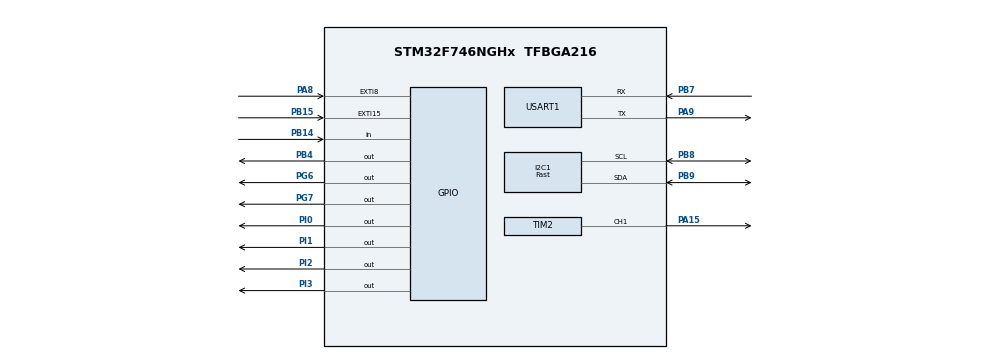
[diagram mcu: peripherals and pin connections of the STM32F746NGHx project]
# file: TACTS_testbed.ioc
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CORTEX_M7.CPU_DCache=Enabled
CORTEX_M7.CPU_ICache=Enabled
I2C1.I2C_Speed_Mode=I2C_Fast
I2C1.Timing=0x6000030D
Mcu.Family=STM32F7
Mcu.Name=STM32F746NGHx
Mcu.Package=TFBGA216
NVIC.EXTI15_10_IRQn=true\:0\:0\:false\:true\:true\:4\:true\:true\:true
NVIC.EXTI9_5_IRQn=true\:0\:0\:false\:true\:true\:5\:true\:true\:true
NVIC.I2C1_ER_IRQn=true\:0\:0\:false\:true\:true\:2\:true\:true\:true
NVIC.I2C1_EV_IRQn=true\:0\:0\:false\:true\:true\:3\:true\:true\:true
NVIC.PriorityGroup=NVIC_PRIORITYGROUP_4
NVIC.TIM2_IRQn=true\:0\:0\:false\:true\:true\:7\:true\:true\:true
NVIC.TIM7_IRQn=true\:0\:0\:false\:true\:true\:6\:true\:true\:true
NVIC.USART1_IRQn=true\:0\:0\:false\:true\:true\:1\:true\:true\:true
PA15.Signal=S_TIM2_CH1_ETR
PA8.GPIO_PuPd=GPIO_PULLUP
PA8.Signal=GPXTI8
PA9.Mode=Asynchronous
PA9.Signal=USART1_TX
PB14.Signal=GPIO_Input
PB15.GPIO_PuPd=GPIO_PULLUP
PB15.Signal=GPXTI15
PB4.Signal=GPIO_Output
PB7.Mode=Asynchronous
PB7.Signal=USART1_RX
PB8.Mode=I2C
PB8.Signal=I2C1_SCL
PB9.Mode=I2C
PB9.Signal=I2C1_SDA
PG6.Signal=GPIO_Output
PG7.Signal=GPIO_Output
PH0/OSC_IN.Mode=HSE-External-Clock-Source
PH0/OSC_IN.Signal=RCC_OSC_IN
PH1/OSC_OUT.Mode=HSE-External-Clock-Source
PH1/OSC_OUT.Signal=RCC_OSC_OUT
PI0.Signal=GPIO_Output
PI1.Signal=GPIO_Output
PI2.Signal=GPIO_Output
PI3.Signal=GPIO_Output
ProjectManager.HeapSize=0x800
ProjectManager.StackSize=0x800
ProjectManager.TargetToolchain=STM32CubeIDE
RCC.AHBFreq_Value=216000000
RCC.APB1CLKDivider=RCC_HCLK_DIV4
RCC.APB1Freq_Value=54000000
RCC.APB1TimFreq_Value=108000000
RCC.APB2CLKDivider=RCC_HCLK_DIV2
RCC.APB2Freq_Value=108000000
RCC.APB2TimFreq_Value=216000000
RCC.CortexFreq_Value=216000000
RCC.HCLKFreq_Value=216000000
RCC.HSE_VALUE=8000000
RCC.HSI_VALUE=16000000
RCC.LSE_VALUE=32768
RCC.PLLM=4
RCC.PLLN=216
RCC.PLLSourceVirtual=RCC_PLLSOURCE_HSE
RCC.SYSCLKFreq_VALUE=216000000
RCC.SYSCLKSource=RCC_SYSCLKSOURCE_PLLCLK
RCC.USBFreq_Value=216000000
RCC.VCOOutputFreq_Value=432000000
SH.S_TIM2_CH1_ETR.0=TIM2_CH1,PWM Generation1 CH1
STMicroelectronics.X-CUBE-AI.8.1.0.ActivationBufferSizeList=4504
STMicroelectronics.X-CUBE-AI.8.1.0.ActivationBuffers=pool0
STMicroelectronics.X-CUBE-AI.8.1.0.ActivationNames=pool0
STMicroelectronics.X-CUBE-AI.8.1.0.ActivationSizes=AI_TWOLINE_DATA_ACTIVATION_1_SIZE
STMicroelectronics.X-CUBE-AI.8.1.0.HeapSize=0x800
STMicroelectronics.X-CUBE-AI.8.1.0.InternalRamActivationBufferMaxSize=AI_TWOLINE_DATA_ACTIVATIONS_SIZE
STMicroelectronics.X-CUBE-AI.8.1.0.LatestDirectoryUsed-b0c1ff3c262577b753a2ad53dde2fbe0ad325509017b4415ac4ec1ed1279039b=D\:\\ME program\\2017-PhD\\01_research\\02Study\\34_ballon_like_cover\\DeepLearing\\TACTS\\MicroController\\STM32F746\\TACTS_testbed
STMicroelectronics.X-CUBE-AI.8.1.0.MaximumNumberOfInputLayer=1
STMicroelectronics.X-CUBE-AI.8.1.0.MaximumNumberOfOutputLayer=1
STMicroelectronics.X-CUBE-AI.8.1.0.MaximumSizeOfInputLayer=1
STMicroelectronics.X-CUBE-AI.8.1.0.MaximumSizeOfOutputLayer=1
STMicroelectronics.X-CUBE-AI.8.1.0.ModelActualCompression-b0c1ff3c262577b753a2ad53dde2fbe0ad325509017b4415ac4ec1ed1279039b=0.0
STMicroelectronics.X-CUBE-AI.8.1.0.ModelCompression-b0c1ff3c262577b753a2ad53dde2fbe0ad325509017b4415ac4ec1ed1279039b=None
STMicroelectronics.X-CUBE-AI.8.1.0.ModelFlashOccupation-b0c1ff3c262577b753a2ad53dde2fbe0ad325509017b4415ac4ec1ed1279039b=105179
STMicroelectronics.X-CUBE-AI.8.1.0.ModelHashList=b0c1ff3c262577b753a2ad53dde2fbe0ad325509017b4415ac4ec1ed1279039b
STMicroelectronics.X-CUBE-AI.8.1.0.ModelKind-b0c1ff3c262577b753a2ad53dde2fbe0ad325509017b4415ac4ec1ed1279039b=TFLITE
STMicroelectronics.X-CUBE-AI.8.1.0.ModelMacc-b0c1ff3c262577b753a2ad53dde2fbe0ad325509017b4415ac4ec1ed1279039b=83836
STMicroelectronics.X-CUBE-AI.8.1.0.ModelName-b0c1ff3c262577b753a2ad53dde2fbe0ad325509017b4415ac4ec1ed1279039b=twoline
STMicroelectronics.X-CUBE-AI.8.1.0.ModelNameList=twoline
STMicroelectronics.X-CUBE-AI.8.1.0.ModelRamOccupation-b0c1ff3c262577b753a2ad53dde2fbe0ad325509017b4415ac4ec1ed1279039b=4504
STMicroelectronics.X-CUBE-AI.8.1.0.ModelStructureFile-b0c1ff3c262577b753a2ad53dde2fbe0ad325509017b4415ac4ec1ed1279039b=1110_3.6kPa_5V_2line_B9.tflite
STMicroelectronics.X-CUBE-AI.8.1.0.ModelType-b0c1ff3c262577b753a2ad53dde2fbe0ad325509017b4415ac4ec1ed1279039b=STM32Cube.AI runtime
STMicroelectronics.X-CUBE-AI.8.1.0.ReadyForCodeGeneration=true
STMicroelectronics.X-CUBE-AI.8.1.0.StackSize=0x800
STMicroelectronics.X-CUBE-AI.8.1.0.WorkingBufferStartAddrList=0xFFFFFFFF
STMicroelectronics.X-CUBE-AI.8.1.0.XAaCUBEAaAICcArtificialOoIntelligenceJjCore=true
STMicroelectronics.X-CUBE-AI.8.1.0.copyWeightToRam=false
STMicroelectronics.X-CUBE-AI.8.1.0.customLayerConfigEnabled=false
STMicroelectronics.X-CUBE-AI.8.1.0.noOnnxIoTranspose=false
STMicroelectronics.X-CUBE-AI.8.1.0.useInputAllocation=true
STMicroelectronics.X-CUBE-AI.8.1.0.useOutputAllocation=true
TIM2.Channel-PWM\ Generation1\ CH1=TIM_CHANNEL_1
TIM2.Period=50-1
TIM2.Prescaler=10800-1
TIM7.Period=50-1
TIM7.Prescaler=10800-1
USART1.VirtualMode-Asynchronous=VM_ASYNC
VP_CRC_VS_CRC.Mode=CRC_Activate
VP_STMicroelectronics.X-CUBE-AI_VS_ArtificialOoIntelligenceJjXAaCUBEAaAI_8.1.0_8.1.0.Mode=ArtificialOoIntelligenceJjXAaCUBEAaAI
VP_TIM2_VS_ClockSourceINT.Mode=Internal
VP_TIM7_VS_ClockSourceINT.Mode=Enable_Timer
board=custom

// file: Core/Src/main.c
/* USER CODE BEGIN Header */
/**
  ******************************************************************************
  * @file           : main.c
  * @brief          : Main program body
  ******************************************************************************
  * @attention
  *
  * Copyright (c) 2023 STMicroelectronics.
  * All rights reserved.
  *
  * This software is licensed under terms that can be found in the LICENSE file
  * in the root directory of this software component.
  * If no LICENSE file comes with this software, it is provided AS-IS.
  *
  ******************************************************************************
  */
/* USER CODE END Header */
#include "main.h"
#include "i2c.h"
#include "tim.h"
#include "usart.h"
#include "gpio.h"

/* USER CODE BEGIN Includes */

#include <stdio.h>
#include <stdlib.h>
#include "motor.h"
#include "hx711.h"
#include <string.h>
#include "kalman.h"
#include "vl53l0x_api.h"
#include <math.h>
#include "avgstd.h"

/* USER CODE END Includes */

/* USER CODE BEGIN PV */

/* USER CODE BEGIN Init */

HAL_StatusTypeDef status;

uint32_t time_diff =0;
uint32_t start_time =0;
uint32_t end_time =0;

uint32_t start_section_time = 0;
uint32_t end_section_time = 0;
uint32_t elapsed_section_time =0;

/* USER CODE END PV */

void SystemClock_Config(void);
static void MX_NVIC_Init(void);
/* USER CODE BEGIN PFP */
void ProcessCommand(uint8_t *command);
void RevCommand(char *arg);
void LinCommand();
void ServoCommand();
void SensorCommand();
void AutoCommand();
void InitializaionCalibrationCommand();
void CalibrationCommand();
void SetSensorCommand();
void AvgStdCommand();
void ZeroCommand();

/* USER CODE END PFP */

/* USER CODE BEGIN 0 */

void ProcessCommand(uint8_t *commandBuffer)
{
    char *command = strtok((char*)commandBuffer, " "); // Command separation
    // 'strtok'는 다음 호출 때 NULL을 사용하여 이전 문자열에서 계속 토큰을 추출
    char *argument = strtok(NULL, " "); // argument seperation

    if (strcmp((char*)command, "echo") == 0) {HAL_UART_Transmit(&huart1, txMsg, sprintf((char*)txMsg, "echo\n"), 100);}
    else if (strcmp((char*)command, "rev") == 0) {RevCommand(argument);}
    else if (strcmp((char*)command, "lin") == 0) {LinCommand(argument);}
    else if (strcmp((char*)command, "servo") == 0) {ServoCommand(argument);}
    else if (strcmp((char*)command, "sensor") == 0) {SensorCommand();}
    else if (strcmp((char*)command, "cali") == 0) {CalibrationCommand();}
    else if (strcmp((char*)command, "ini") == 0) {InitializaionCalibrationCommand();}
    else if (strcmp((char*)command, "setsensor") == 0) {SetSensorCommand();}
    else if (strcmp((char*)command, "auto") == 0) {AutoCommand();}
    else if (strcmp((char*)command, "zero") == 0) {ZeroCommand();}
    else if (strcmp((char*)command, "4") == 0) {CalibrationCommand();}
    else {HAL_UART_Transmit(&huart1, txMsg, sprintf((char*)txMsg, "Please insert correct command\n"), 100);}
}

void RevCommand(char *arg){
    int step_rev_angle;
    uint32_t startTime, endTime, elapsedTime;
    if(sscanf(arg, "%d", &step_rev_angle) == 1){
        startTime = HAL_GetTick();
		HAL_UART_Transmit(&huart1, (uint8_t*)txMsg, sprintf((char*)txMsg, "%d deg revolution Start \n\r",step_rev_angle), 100);
        stepRev(step_rev_angle);
		HAL_UART_Transmit(&huart1, (uint8_t*)txMsg, sprintf((char*)txMsg, "%d deg revolution End \n\r",step_rev_angle), 100);
		endTime = HAL_GetTick();
		elapsedTime = endTime - startTime;
        HAL_UART_Transmit(&huart1, (uint8_t*)txMsg, sprintf((char*)txMsg, "Elapsed Time: %lu ms\n\r", elapsedTime), 100);
    }else{
    	HAL_UART_Transmit(&huart1, (uint8_t*)txMsg, sprintf((char*)txMsg, "invalid data\r\n"), 100);
    }
    HAL_Delay(1000); // Delay for 1 second
}

void LinCommand(char *arg){
    int step_lin_dist = 0;
    uint32_t startTime, endTime, elapsedTime;
    if (sscanf(arg, "%d", &step_lin_dist) == 1) {
        startTime = HAL_GetTick();
		HAL_UART_Transmit(&huart1, (uint8_t*)txMsg, sprintf((char*)txMsg, "%d mm lin Still moving \n\r",step_lin_dist), 100);
        stepLin(step_lin_dist);
        HAL_UART_Transmit(&huart1, (uint8_t*)txMsg, sprintf((char*)txMsg, "%d mm lin End\n\r", step_lin_dist), 100);
		endTime = HAL_GetTick();
		elapsedTime = endTime - startTime;
        HAL_UART_Transmit(&huart1, (uint8_t*)txMsg, sprintf((char*)txMsg, "Elapsed Time: %lu ms\n\r", elapsedTime), 100);
    } else {
        HAL_UART_Transmit(&huart1, (uint8_t*)txMsg, sprintf((char*)txMsg, "invalid data\r\n"), 100);
    }
    HAL_Delay(1000); // Delay for 1 second
}

void ServoCommand(char *arg){
    float servo_angle_val = 0;
    if(sscanf(arg, "%f", &servo_angle_val) == 1) {
    	HAL_UART_Transmit(&huart1, (uint8_t*)txMsg, sprintf((char*)txMsg, "%.2f servo Still moving \n\r", servo_angle_val), 100);
    	servo_angle(&htim2, TIM_CHANNEL_1, servo_angle_val);
    	HAL_UART_Transmit(&huart1, (uint8_t*)txMsg, sprintf((char*)txMsg, "%.2f servo End \n\r", servo_angle_val), 100);
        HAL_Delay(2000); // Delay for 2 seconds
        servo_angle(&htim2, TIM_CHANNEL_1, 0); // return to servo origin
    }else{
        HAL_UART_Transmit(&huart1, (uint8_t*)txMsg, sprintf((char*)txMsg, "invalid data\r\n"), 100);
    }
}

void SensorCommand(){

	ResetAllDevices();
    HAL_UART_Transmit(&huart1, (uint8_t*)txMsg, sprintf((char*)txMsg, "sensor test\r\n"), 100);
    uint32_t startTime, endTime, diffTime;
    for(int count =0; count < NUM_READINGS; count++){
    	uint8_t sensorCount = 0;
    	startTime = HAL_GetTick();
		for (int i = 0; i < NUM_SENSOR; i++) {
			uint8_t q = i / 12;
			uint8_t r = i % 12;
			uint8_t active_device = q * 2 + (r >= 8 ? 1 : 0);
			uint8_t channel = (r >= 8) ? r - 8 : r;
			ResetDevicesExcept(active_device);
			setActiveTcaChannel(active_device, channel);
			Dev = &vl53l0x_s[i];
			VL53L0X_PerformContinuousRangingMeasurement(Dev, &RangingData); // 1500us
			if (RangingData.RangeStatus == 0) {
			  if (RangingData.RangeMilliMeter < 80) {
				  float filteredValue = Kalman_Estimate(&filters[i], RangingData.RangeMilliMeter);
				  HAL_UART_Transmit(&huart1, (uint8_t*)txMsg, sprintf((char*)txMsg, "%.1f ", filteredValue), 500);
				  sensorValues[i][readingCount[i]] = filteredValue;
				  readingCount[i]++;
				  sensorCount++;
			  }
			}else{
				  HAL_UART_Transmit(&huart1, (uint8_t*)txMsg, sprintf((char*)txMsg, "%d ", RangingData.RangeStatus), 500);
				  // 1 : Sigma Fail | 2 : Signal Fail | 3 : Min Range Fail | 4 : Phase Fail | 5 : Hardware Fail | 255 : No update
			  }
		}
		endTime = HAL_GetTick();
		diffTime = endTime - startTime;
		HAL_UART_Transmit(&huart1, (uint8_t*)txMsg, sprintf((char*)txMsg, "%lu ms ", diffTime), 100);

		Hx711Data = Read_HX711();
		UART_SendWeight_g(Hx711Data,-1/1600.00f,10002); // Send the weight data over UART
		HAL_UART_Transmit(&huart1, (uint8_t*)txMsg, sprintf((char*)txMsg, " %d", sensorCount), 100);
		HAL_UART_Transmit(&huart1, (uint8_t*)txMsg, sprintf((char*)txMsg, "\n"), 100);

    }
    TransmitStats();
    ResetSensorData();

}

void ZeroCommand(){
	 for(int count = 0; count < 115200; count++){
		  for (int i = 0; i < NUM_SENSOR; i++) {
			uint8_t q = i / 12;
			uint8_t r = i % 12;
			uint8_t active_device = q * 2 + (r >= 8 ? 1 : 0);
			uint8_t channel = (r >= 8) ? r - 8 : r;
			ResetDevicesExcept(active_device);
	        setActiveTcaChannel(active_device,channel);
			Dev = &vl53l0x_s[i];
			VL53L0X_PerformContinuousRangingMeasurement(Dev, &RangingData); // 1500us
			if (RangingData.RangeStatus == 0) {
			  if (RangingData.RangeMilliMeter < 80) {
				  float filteredValue = Kalman_Estimate(&filters[i], RangingData.RangeMilliMeter);
				  HAL_UART_Transmit(&huart1, (uint8_t*)txMsg, sprintf((char*)txMsg, "%.2f ", filteredValue), 500);
			  }
			}
		  }
	  HAL_UART_Transmit(&huart1, (uint8_t*)txMsg, sprintf((char*)txMsg, "0 0 0 0\n"), 500);
	 }
}

void AutoCommand(){

    HAL_UART_Transmit(&huart1, (uint8_t*)txMsg, sprintf((char*)txMsg, "Auto Command \r\n"), 100);

	ResetAllDevices();
    for(int count =0; count < 100; count++){
		for (int i = 0; i < NUM_SENSOR; i++) {
			uint8_t q = i / 12;
			uint8_t r = i % 12;
			uint8_t active_device = q * 2 + (r >= 8 ? 1 : 0);
			uint8_t channel = (r >= 8) ? r - 8 : r;
			ResetDevicesExcept(active_device);
			setActiveTcaChannel(active_device, channel);
			Dev = &vl53l0x_s[i];
			VL53L0X_PerformContinuousRangingMeasurement(Dev, &RangingData); // 1500us
			if (RangingData.RangeStatus == 0) {
			  if (RangingData.RangeMilliMeter < 80) {
				  float filteredValue = Kalman_Estimate(&filters[i], RangingData.RangeMilliMeter);
				  HAL_UART_Transmit(&huart1, (uint8_t*)txMsg, sprintf((char*)txMsg, "%.1f ", filteredValue), 500);
			  }
			}else{
				  HAL_UART_Transmit(&huart1, (uint8_t*)txMsg, sprintf((char*)txMsg, "%d ", RangingData.RangeStatus), 500);
				  // 1 : Sigma Fail | 2 : Signal Fail | 3 : Min Range Fail | 4 : Phase Fail | 5 : Hardware Fail | 255 : No update
			  }

		}
		HAL_UART_Transmit(&huart1, (uint8_t*)txMsg, sprintf((char*)txMsg, "\n"), 100);

    }

	HAL_UART_Transmit(&huart1, (uint8_t*)txMsg, sprintf((char*)txMsg, "autoMode\r\n"), 100);
	ResetAllDevices();

	float forceSensorZeroPoint = 0.0f;

	servo_angle(&htim2, TIM_CHANNEL_1, 1); // poking
  	 for(int lin = 0; lin < 21; lin ++){
		 for(int rev = 0; rev < 72; rev++){
			 for(int r = 0; r < 8; r++){
				 servo_angle(&htim2, TIM_CHANNEL_1, r); // poking
				 HAL_Delay(500);
				 for(int count = 0; count < 40; count++){
					  for (int i = 0; i < NUM_SENSOR; i++) {
						uint8_t q = i / 12;
						uint8_t r = i % 12;
						uint8_t active_device = q * 2 + (r >= 8 ? 1 : 0);
						uint8_t channel = (r >= 8) ? r - 8 : r;
						ResetDevicesExcept(active_device);
				        setActiveTcaChannel(active_device,channel);
						Dev = &vl53l0x_s[i];
						VL53L0X_PerformContinuousRangingMeasurement(Dev, &RangingData); // 1500us
						if (RangingData.RangeStatus == 0) {
						  if (RangingData.RangeMilliMeter < 80) {
							  float filteredValue = Kalman_Estimate(&filters[i], RangingData.RangeMilliMeter);
							  HAL_UART_Transmit(&huart1, (uint8_t*)txMsg, sprintf((char*)txMsg, "%.2f ", filteredValue), 500);
						  }
						}else{
							  //HAL_UART_Transmit(&huart1, (uint8_t*)txMsg, sprintf((char*)txMsg, "%d ", RangingData.RangeStatus), 500);
							  // 1 : Sigma Fail | 2 : Signal Fail | 3 : Min Range Fail | 4 : Phase Fail | 5 : Hardware Fail | 255 : No update
						  }
					  }

				if (r == 0) {
					forceSensorZeroPoint = Read_HX711();
					Hx711Data = 0;
				} else {
					Hx711Data = Read_HX711() - forceSensorZeroPoint;
				}

				  UART_SendWeight_g(Hx711Data,-1/1600.00f,0); // Send the weight data over UART
				  HAL_UART_Transmit(&huart1, (uint8_t*)txMsg, sprintf((char*)txMsg, " %d %d %.2f\n", 8*lin+7, 20*rev, r*0.8), 500);
				 }
			 HAL_Delay(500);
			 servo_angle(&htim2, TIM_CHANNEL_1, 0); // turn to origin
			 HAL_Delay(500);
			 }
			 stepRev(20); // revolution
		 }
		 HAL_Delay(500);
		 stepRev(-360);
		 stepLin(-8); // moving horizontal
  	 }
}

void InitializaionCalibrationCommand()
{
	HAL_UART_Transmit(&huart1, (uint8_t*)txMsg, sprintf((char*)txMsg, "InitializationCommand\n\r"), 100);

	ResetAllDevices();
  	for (int i = 0; i < NUM_SENSOR; i++) {
  	    uint8_t q = i / 12;
  	    uint8_t r = i % 12;
  	    uint8_t active_device = q * 2 + (r >= 8 ? 1 : 0);
  	    uint8_t channel = (r >= 8) ? r - 8 : r;

        ResetDevicesExcept(active_device);
        setActiveTcaChannel(active_device,channel);

  		Dev = &vl53l0x_s[i];
  		Dev->I2cHandle = &hi2c1;
  		Dev->I2cDevAddr = VL53L0X_ADDR;

  		VL53L0X_WaitDeviceBooted( Dev );
  		VL53L0X_DataInit( Dev );
  		VL53L0X_StaticInit( Dev );
  		VL53L0X_SetDeviceMode(Dev, VL53L0X_DEVICEMODE_CONTINUOUS_RANGING);

  		VL53L0X_PerformRefSpadManagement( Dev, &refSpadCount[i], &isApertureSpads[i]);
  		VL53L0X_PerformRefCalibration( Dev, &VhvSettings[i], &PhaseCal[i]);

  		refSpadCountHost[i] = refSpadCount[i];
  		isApertureSpadsHost[i] = isApertureSpads[i];
  		VhvSettingsHost[i] = VhvSettings[i];
  		PhaseCalHost[i] = PhaseCal[i];

  		VL53L0X_SetLimitCheckEnable( Dev, VL53L0X_CHECKENABLE_SIGMA_FINAL_RANGE, 1);
  		VL53L0X_SetLimitCheckEnable( Dev, VL53L0X_CHECKENABLE_SIGNAL_RATE_FINAL_RANGE, 1);
  		VL53L0X_SetLimitCheckValue( Dev, VL53L0X_CHECKENABLE_SIGNAL_RATE_FINAL_RANGE, (FixPoint1616_t)(0.1*65536));
  		VL53L0X_SetLimitCheckValue( Dev, VL53L0X_CHECKENABLE_SIGMA_FINAL_RANGE, (FixPoint1616_t)(60*65536));
  		VL53L0X_SetMeasurementTimingBudgetMicroSeconds( Dev, 33000);
  		VL53L0X_SetVcselPulsePeriod( Dev, VL53L0X_VCSEL_PERIOD_PRE_RANGE, 18);
  		VL53L0X_SetVcselPulsePeriod( Dev, VL53L0X_VCSEL_PERIOD_FINAL_RANGE, 14);

		Kalman_Init(&filters[i], Q, R, P, 0);  // Q, R, P, 초기값

 		HAL_UART_Transmit(&huart1, (uint8_t*)txMsg, sprintf((char*)txMsg, "%02d ",i), 100);
 		if(i%12 ==11){HAL_UART_Transmit(&huart1, (uint8_t*)txMsg, sprintf((char*)txMsg, "\n\r"), 100);}
  	}

	HAL_UART_Transmit(&huart1, (uint8_t*)txMsg, sprintf((char*)txMsg, "uint32_t refSpadCountHost[NUM_SENSOR]={"), 100);
	for (int i = 0; i < NUM_SENSOR; i++){
		if(i < NUM_SENSOR - 1){
			HAL_UART_Transmit(&huart1, (uint8_t*)txMsg, sprintf((char*)txMsg, "%lu,",refSpadCount[i]), 100);
		} else {
			HAL_UART_Transmit(&huart1, (uint8_t*)txMsg, sprintf((char*)txMsg, "%lu};\n",refSpadCount[i]), 100);
		}
	}

	HAL_UART_Transmit(&huart1, (uint8_t*)txMsg, sprintf((char*)txMsg, "uint8_t isApertureSpadsHost[NUM_SENSOR]={"), 100);
	for (int i = 0; i < NUM_SENSOR; i++){
		if(i < NUM_SENSOR - 1){
			HAL_UART_Transmit(&huart1, (uint8_t*)txMsg, sprintf((char*)txMsg, "%d,",isApertureSpads[i]), 100);
		} else {
			HAL_UART_Transmit(&huart1, (uint8_t*)txMsg, sprintf((char*)txMsg, "%d};\n",isApertureSpads[i]), 100);
		}
	}

	HAL_UART_Transmit(&huart1, (uint8_t*)txMsg, sprintf((char*)txMsg, "uint8_t VhvSettingsHost[NUM_SENSOR]={"), 100);
	for (int i = 0; i < NUM_SENSOR; i++){
		if(i < NUM_SENSOR - 1){
			HAL_UART_Transmit(&huart1, (uint8_t*)txMsg, sprintf((char*)txMsg, "%d,",VhvSettings[i]), 100);
		} else {
			HAL_UART_Transmit(&huart1, (uint8_t*)txMsg, sprintf((char*)txMsg, "%d};\n",VhvSettings[i]), 100);
		}
	}

	HAL_UART_Transmit(&huart1, (uint8_t*)txMsg, sprintf((char*)txMsg, "uint8_t PhaseCalHost[NUM_SENSOR]={"), 100);
	for (int i = 0; i < NUM_SENSOR; i++){
		if(i < NUM_SENSOR - 1){
			HAL_UART_Transmit(&huart1, (uint8_t*)txMsg, sprintf((char*)txMsg, "%d,",PhaseCal[i]), 100);
		} else {
			HAL_UART_Transmit(&huart1, (uint8_t*)txMsg, sprintf((char*)txMsg, "%d};\n",PhaseCal[i]), 100);
		}
	}

}

void CalibrationCommand() {
}
void AvgStdCommand() {
}
void SetSensorCommand(){
	HAL_UART_Transmit(&huart1, (uint8_t*)txMsg, sprintf((char*)txMsg, "SetCommand\n\r"), 100);

	ResetAllDevices();
  	for (int i = 0; i < NUM_SENSOR; i++) {
  	    uint8_t q = i / 12;
  	    uint8_t r = i % 12;
  	    uint8_t active_device = q * 2 + (r >= 8 ? 1 : 0);
  	    uint8_t channel = (r >= 8) ? r - 8 : r;

        ResetDevicesExcept(active_device);
        setActiveTcaChannel(active_device,channel);

  		Dev = &vl53l0x_s[i];
  		Dev->I2cHandle = &hi2c1;
  		Dev->I2cDevAddr = VL53L0X_ADDR;

  		VL53L0X_WaitDeviceBooted( Dev );
  		VL53L0X_DataInit( Dev );
  		VL53L0X_StaticInit( Dev );
  		VL53L0X_SetDeviceMode(Dev, VL53L0X_DEVICEMODE_CONTINUOUS_RANGING);

		VL53L0X_SetReferenceSpads(Dev, refSpadCountHost[i], isApertureSpadsHost[i]);
  		VL53L0X_SetRefCalibration(Dev, VhvSettingsHost[i], PhaseCalHost[i]);

  		VL53L0X_SetLimitCheckEnable(Dev, VL53L0X_CHECKENABLE_SIGMA_FINAL_RANGE, 1);
  		VL53L0X_SetLimitCheckEnable(Dev, VL53L0X_CHECKENABLE_SIGNAL_RATE_FINAL_RANGE, 1);
  		VL53L0X_SetLimitCheckValue(Dev, VL53L0X_CHECKENABLE_SIGNAL_RATE_FINAL_RANGE, (FixPoint1616_t)(0.1*65536));
  		VL53L0X_SetLimitCheckValue(Dev, VL53L0X_CHECKENABLE_SIGMA_FINAL_RANGE, (FixPoint1616_t)(60*65536));
  		VL53L0X_SetMeasurementTimingBudgetMicroSeconds(Dev, 33000);
  		VL53L0X_SetVcselPulsePeriod(Dev, VL53L0X_VCSEL_PERIOD_PRE_RANGE, 18);
  		VL53L0X_SetVcselPulsePeriod(Dev, VL53L0X_VCSEL_PERIOD_FINAL_RANGE, 14);

		Kalman_Init(&filters[i], Q, R, P, 0);  // Q, R, P, 초기값

 		HAL_UART_Transmit(&huart1, (uint8_t*)txMsg, sprintf((char*)txMsg, "%02d:(",i), 100);
 		HAL_UART_Transmit(&huart1, (uint8_t*)txMsg, sprintf((char*)txMsg, "%02lu ",refSpadCountHost[i]), 100);
 		HAL_UART_Transmit(&huart1, (uint8_t*)txMsg, sprintf((char*)txMsg, "%02d ",isApertureSpadsHost[i]), 100);
 		HAL_UART_Transmit(&huart1, (uint8_t*)txMsg, sprintf((char*)txMsg, "%02d ",VhvSettingsHost[i]), 100);
 		HAL_UART_Transmit(&huart1, (uint8_t*)txMsg, sprintf((char*)txMsg, "%02d) ",PhaseCalHost[i]), 100);
 		if(i%12 ==11){HAL_UART_Transmit(&huart1, (uint8_t*)txMsg, sprintf((char*)txMsg, "\n\r"), 100);}

  	}
}

/* USER CODE END 0 */

int main(void)
{

  /* MCU Configuration--------------------------------------------------------*/

  /* Reset of all peripherals, Initializes the Flash interface and the Systick. */
  HAL_Init();

  /* USER CODE END Init */

  /* Configure the system clock */
  SystemClock_Config();

  /* Initialize all configured peripherals */
  MX_GPIO_Init();
  MX_I2C1_Init();
  MX_TIM7_Init();
  MX_USART1_UART_Init();
  MX_TIM2_Init();

  /* Initialize interrupts */
  MX_NVIC_Init();
  /* USER CODE BEGIN 2 */

  HAL_TIM_PWM_Start(&htim2,TIM_CHANNEL_1);

  // Initialize the HX711
  HX711_Init();

  /* UART interrupt initialization */
  HAL_UART_Transmit(&huart1, (uint8_t*)txMsg, sprintf((char*)txMsg, "JH TACTS test\n\r"), 100);
  startMsg();

  /* USER CODE END 2 */

  /* Infinite loop */
  /* USER CODE BEGIN WHILE */

  while (1)
  {
	  if(ReceiveUartMessage(&huart1, rxMsg, sizeof(rxMsg)) == HAL_OK)
	  {
	      ProcessCommand(rxMsg);
	  }

    /* USER CODE END WHILE */

  }
}

void SystemClock_Config(void)
{
  RCC_OscInitTypeDef RCC_OscInitStruct = {0};
  RCC_ClkInitTypeDef RCC_ClkInitStruct = {0};

  /** Configure the main internal regulator output voltage
  */
  __HAL_RCC_PWR_CLK_ENABLE();
  __HAL_PWR_VOLTAGESCALING_CONFIG(PWR_REGULATOR_VOLTAGE_SCALE1);

  /** Initializes the RCC Oscillators according to the specified parameters
  * in the RCC_OscInitTypeDef structure.
  */
  RCC_OscInitStruct.OscillatorType = RCC_OSCILLATORTYPE_HSE;
  RCC_OscInitStruct.HSEState = RCC_HSE_ON;
  RCC_OscInitStruct.PLL.PLLState = RCC_PLL_ON;
  RCC_OscInitStruct.PLL.PLLSource = RCC_PLLSOURCE_HSE;
  RCC_OscInitStruct.PLL.PLLM = 25;
  RCC_OscInitStruct.PLL.PLLN = 432;
  RCC_OscInitStruct.PLL.PLLP = RCC_PLLP_DIV2;
  RCC_OscInitStruct.PLL.PLLQ = 2;
  if (HAL_RCC_OscConfig(&RCC_OscInitStruct) != HAL_OK)
  {
    Error_Handler();
  }

  /** Activate the Over-Drive mode
  */
  if (HAL_PWREx_EnableOverDrive() != HAL_OK)
  {
    Error_Handler();
  }

  /** Initializes the CPU, AHB and APB buses clocks
  */
  RCC_ClkInitStruct.ClockType = RCC_CLOCKTYPE_HCLK|RCC_CLOCKTYPE_SYSCLK
                              |RCC_CLOCKTYPE_PCLK1|RCC_CLOCKTYPE_PCLK2;
  RCC_ClkInitStruct.SYSCLKSource = RCC_SYSCLKSOURCE_PLLCLK;
  RCC_ClkInitStruct.AHBCLKDivider = RCC_SYSCLK_DIV1;
  RCC_ClkInitStruct.APB1CLKDivider = RCC_HCLK_DIV4;
  RCC_ClkInitStruct.APB2CLKDivider = RCC_HCLK_DIV2;

  if (HAL_RCC_ClockConfig(&RCC_ClkInitStruct, FLASH_LATENCY_7) != HAL_OK)
  {
    Error_Handler();
  }
}

/**
  * @brief NVIC Configuration.
  * @retval None
  */
static void MX_NVIC_Init(void)
{
  /* USART1_IRQn interrupt configuration */
  HAL_NVIC_SetPriority(USART1_IRQn, 0, 0);
  HAL_NVIC_EnableIRQ(USART1_IRQn);
  /* I2C1_ER_IRQn interrupt configuration */
  HAL_NVIC_SetPriority(I2C1_ER_IRQn, 0, 0);
  HAL_NVIC_EnableIRQ(I2C1_ER_IRQn);
  /* I2C1_EV_IRQn interrupt configuration */
  HAL_NVIC_SetPriority(I2C1_EV_IRQn, 0, 0);
  HAL_NVIC_EnableIRQ(I2C1_EV_IRQn);
  /* EXTI15_10_IRQn interrupt configuration */
  HAL_NVIC_SetPriority(EXTI15_10_IRQn, 0, 0);
  HAL_NVIC_EnableIRQ(EXTI15_10_IRQn);
  /* EXTI9_5_IRQn interrupt configuration */
  HAL_NVIC_SetPriority(EXTI9_5_IRQn, 0, 0);
  HAL_NVIC_EnableIRQ(EXTI9_5_IRQn);
  /* TIM7_IRQn interrupt configuration */
  HAL_NVIC_SetPriority(TIM7_IRQn, 0, 0);
  HAL_NVIC_EnableIRQ(TIM7_IRQn);
  /* TIM2_IRQn interrupt configuration */
  HAL_NVIC_SetPriority(TIM2_IRQn, 0, 0);
  HAL_NVIC_EnableIRQ(TIM2_IRQn);
}

void Error_Handler(void)
{
  __disable_irq();
  while (1)
  {
  }
}
